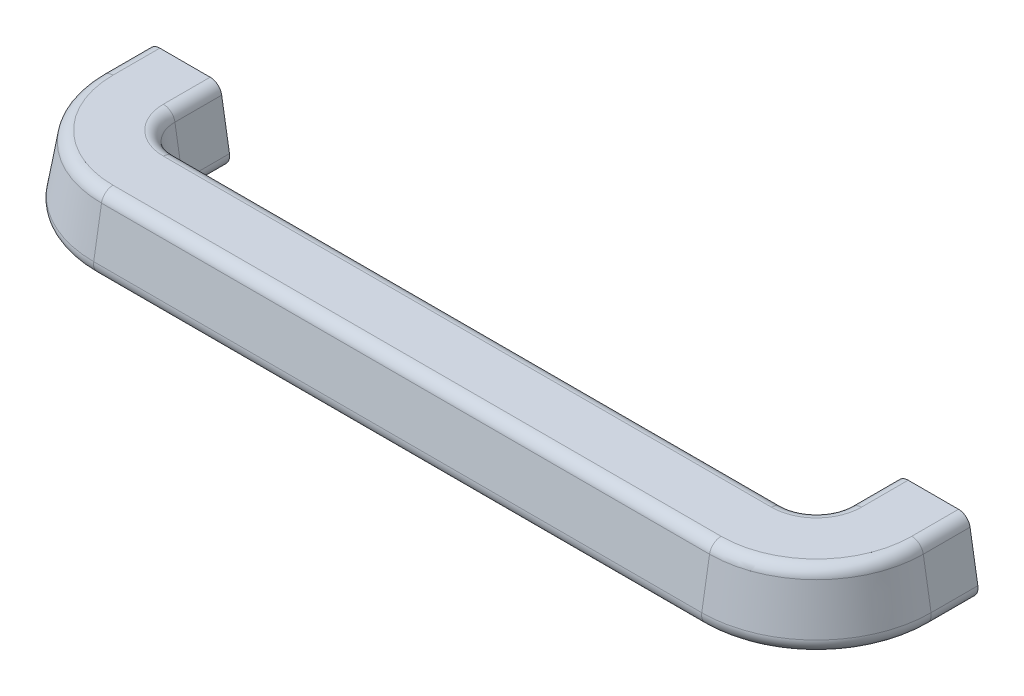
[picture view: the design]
ISO-10303-21;
HEADER;
FILE_DESCRIPTION(('STEP AP214'),'2;1');
FILE_NAME('part.step','',(''),(''),'','','');
FILE_SCHEMA(('AUTOMOTIVE_DESIGN { 1 0 10303 214 1 1 1 1 }'));
ENDSEC;
DATA;
#1=APPLICATION_CONTEXT('core data for automotive mechanical design processes');
#2=APPLICATION_PROTOCOL_DEFINITION('international standard','automotive_design',2000,#1);
#3=PRODUCT_CONTEXT('',#1,'mechanical');
#4=PRODUCT('Part','Part','',(#3));
#5=PRODUCT_RELATED_PRODUCT_CATEGORY('part','',(#4));
#6=PRODUCT_DEFINITION_FORMATION('','',#4);
#7=PRODUCT_DEFINITION_CONTEXT('part definition',#1,'design');
#8=PRODUCT_DEFINITION('design','',#6,#7);
#9=PRODUCT_DEFINITION_SHAPE('','',#8);
#10=(LENGTH_UNIT() NAMED_UNIT(*) SI_UNIT(.MILLI.,.METRE.));
#11=(NAMED_UNIT(*) PLANE_ANGLE_UNIT() SI_UNIT($,.RADIAN.));
#12=(NAMED_UNIT(*) SI_UNIT($,.STERADIAN.) SOLID_ANGLE_UNIT());
#13=UNCERTAINTY_MEASURE_WITH_UNIT(LENGTH_MEASURE(1.E-05),#10,'distance_accuracy_value','');
#14=(GEOMETRIC_REPRESENTATION_CONTEXT(3) GLOBAL_UNCERTAINTY_ASSIGNED_CONTEXT((#13)) GLOBAL_UNIT_ASSIGNED_CONTEXT((#10,
#11,#12)) REPRESENTATION_CONTEXT('',''));
#15=CARTESIAN_POINT('',(0.,0.,0.));
#16=DIRECTION('',(0.,0.,1.));
#17=DIRECTION('',(1.,0.,0.));
#18=AXIS2_PLACEMENT_3D('',#15,#16,#17);
#19=CARTESIAN_POINT('',(-189.529257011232,12.7,-38.1));
#20=DIRECTION('',(0.,0.,-1.));
#21=DIRECTION('',(-1.,0.,0.));
#22=AXIS2_PLACEMENT_3D('',#19,#20,#21);
#23=CYLINDRICAL_SURFACE('',#22,6.35);
#24=CARTESIAN_POINT('',(-189.529257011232,12.7,-38.1));
#25=DIRECTION('',(0.,0.,1.));
#26=DIRECTION('',(-1.,0.,0.));
#27=AXIS2_PLACEMENT_3D('',#24,#25,#26);
#28=CIRCLE('',#27,6.35);
#29=CARTESIAN_POINT('',(-183.265655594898,13.743933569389,-38.1));
#30=VERTEX_POINT('',#29);
#31=CARTESIAN_POINT('',(-189.529257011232,19.05,-38.1));
#32=VERTEX_POINT('',#31);
#33=EDGE_CURVE('E505',#30,#32,#28,.T.);
#34=ORIENTED_EDGE('',*,*,#33,.F.);
#35=DIRECTION('',(0.,0.,-1.));
#36=VECTOR('',#35,1.);
#37=CARTESIAN_POINT('',(-183.265655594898,13.743933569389,-38.1));
#38=LINE('',#37,#36);
#39=CARTESIAN_POINT('',(-183.265655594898,13.743933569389,-63.5));
#40=VERTEX_POINT('',#39);
#41=EDGE_CURVE('E595',#30,#40,#38,.T.);
#42=ORIENTED_EDGE('',*,*,#41,.T.);
#43=CARTESIAN_POINT('',(-189.529257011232,12.7,-63.5));
#44=DIRECTION('',(0.,0.,1.));
#45=DIRECTION('',(-1.,0.,0.));
#46=AXIS2_PLACEMENT_3D('',#43,#44,#45);
#47=CIRCLE('',#46,6.35);
#48=CARTESIAN_POINT('',(-189.529257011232,19.05,-63.5));
#49=VERTEX_POINT('',#48);
#50=EDGE_CURVE('E56',#40,#49,#47,.T.);
#51=ORIENTED_EDGE('',*,*,#50,.T.);
#52=DIRECTION('',(0.,0.,-1.));
#53=VECTOR('',#52,1.);
#54=CARTESIAN_POINT('',(-189.529257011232,19.05,-38.1));
#55=LINE('',#54,#53);
#56=EDGE_CURVE('E41',#32,#49,#55,.T.);
#57=ORIENTED_EDGE('',*,*,#56,.F.);
#58=EDGE_LOOP('',(#34,#42,#51,#57));
#59=FACE_BOUND('',#58,.T.);
#60=ADVANCED_FACE('F34',(#59),#23,.T.);
#61=CARTESIAN_POINT('',(-179.032322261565,-11.656066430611,-38.0999999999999));
#62=DIRECTION('',(-0.986393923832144,-0.164398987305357,0.));
#63=DIRECTION('',(0.164398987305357,-0.986393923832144,0.));
#64=AXIS2_PLACEMENT_3D('',#61,#62,#63);
#65=PLANE('',#64);
#66=DIRECTION('',(-0.164398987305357,0.986393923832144,0.));
#67=VECTOR('',#66,1.);
#68=CARTESIAN_POINT('',(-179.032322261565,-11.656066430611,-38.0999999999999));
#69=LINE('',#68,#67);
#70=CARTESIAN_POINT('',(-179.032322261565,-11.656066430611,-38.0999999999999));
#71=VERTEX_POINT('',#70);
#72=EDGE_CURVE('E502',#71,#30,#69,.T.);
#73=ORIENTED_EDGE('',*,*,#72,.F.);
#74=DIRECTION('',(0.,0.,-1.));
#75=VECTOR('',#74,1.);
#76=CARTESIAN_POINT('',(-179.032322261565,-11.656066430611,-38.0999999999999));
#77=LINE('',#76,#75);
#78=CARTESIAN_POINT('',(-179.032322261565,-11.656066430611,-63.4999999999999));
#79=VERTEX_POINT('',#78);
#80=EDGE_CURVE('E592',#71,#79,#77,.T.);
#81=ORIENTED_EDGE('',*,*,#80,.T.);
#82=DIRECTION('',(-0.164398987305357,0.986393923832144,0.));
#83=VECTOR('',#82,1.);
#84=CARTESIAN_POINT('',(-179.032322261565,-11.656066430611,-63.4999999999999));
#85=LINE('',#84,#83);
#86=EDGE_CURVE('E566',#79,#40,#85,.T.);
#87=ORIENTED_EDGE('',*,*,#86,.T.);
#88=ORIENTED_EDGE('',*,*,#41,.F.);
#89=EDGE_LOOP('',(#73,#81,#87,#88));
#90=FACE_BOUND('',#89,.T.);
#91=ADVANCED_FACE('F607',(#90),#65,.F.);
#92=CARTESIAN_POINT('',(-185.295923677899,-12.7,-38.1));
#93=DIRECTION('',(0.,0.,-1.));
#94=DIRECTION('',(-1.,0.,0.));
#95=AXIS2_PLACEMENT_3D('',#92,#93,#94);
#96=CYLINDRICAL_SURFACE('',#95,6.35);
#97=CARTESIAN_POINT('',(-185.295923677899,-12.7,-38.1));
#98=DIRECTION('',(0.,0.,1.));
#99=DIRECTION('',(1.,0.,0.));
#100=AXIS2_PLACEMENT_3D('',#97,#98,#99);
#101=CIRCLE('',#100,6.35);
#102=CARTESIAN_POINT('',(-185.295923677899,-19.05,-38.1));
#103=VERTEX_POINT('',#102);
#104=EDGE_CURVE('E499',#103,#71,#101,.T.);
#105=ORIENTED_EDGE('',*,*,#104,.F.);
#106=DIRECTION('',(0.,0.,-1.));
#107=VECTOR('',#106,1.);
#108=CARTESIAN_POINT('',(-185.295923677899,-19.05,-38.1));
#109=LINE('',#108,#107);
#110=CARTESIAN_POINT('',(-185.295923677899,-19.05,-63.5));
#111=VERTEX_POINT('',#110);
#112=EDGE_CURVE('E589',#103,#111,#109,.T.);
#113=ORIENTED_EDGE('',*,*,#112,.T.);
#114=CARTESIAN_POINT('',(-185.295923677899,-12.7,-63.5));
#115=DIRECTION('',(0.,0.,1.));
#116=DIRECTION('',(1.,0.,0.));
#117=AXIS2_PLACEMENT_3D('',#114,#115,#116);
#118=CIRCLE('',#117,6.35);
#119=EDGE_CURVE('E564',#111,#79,#118,.T.);
#120=ORIENTED_EDGE('',*,*,#119,.T.);
#121=ORIENTED_EDGE('',*,*,#80,.F.);
#122=EDGE_LOOP('',(#105,#113,#120,#121));
#123=FACE_BOUND('',#122,.T.);
#124=ADVANCED_FACE('F613',(#123),#96,.T.);
#125=CARTESIAN_POINT('',(-221.104076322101,-12.7,-38.1000000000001));
#126=DIRECTION('',(0.,0.,-1.));
#127=DIRECTION('',(-1.,0.,0.));
#128=AXIS2_PLACEMENT_3D('',#125,#126,#127);
#129=CYLINDRICAL_SURFACE('',#128,6.35);
#130=CARTESIAN_POINT('',(-221.104076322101,-12.7,-38.1000000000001));
#131=DIRECTION('',(0.,0.,1.));
#132=DIRECTION('',(-1.,0.,0.));
#133=AXIS2_PLACEMENT_3D('',#130,#131,#132);
#134=CIRCLE('',#133,6.35);
#135=CARTESIAN_POINT('',(-227.367677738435,-11.656066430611,-38.1000000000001));
#136=VERTEX_POINT('',#135);
#137=CARTESIAN_POINT('',(-221.104076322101,-19.05,-38.1000000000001));
#138=VERTEX_POINT('',#137);
#139=EDGE_CURVE('E496',#136,#138,#134,.T.);
#140=ORIENTED_EDGE('',*,*,#139,.F.);
#141=DIRECTION('',(0.,0.,-1.));
#142=VECTOR('',#141,1.);
#143=CARTESIAN_POINT('',(-227.367677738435,-11.656066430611,-38.1000000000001));
#144=LINE('',#143,#142);
#145=CARTESIAN_POINT('',(-227.367677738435,-11.656066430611,-63.5000000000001));
#146=VERTEX_POINT('',#145);
#147=EDGE_CURVE('E583',#136,#146,#144,.T.);
#148=ORIENTED_EDGE('',*,*,#147,.T.);
#149=CARTESIAN_POINT('',(-221.104076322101,-12.7,-63.5000000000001));
#150=DIRECTION('',(0.,0.,1.));
#151=DIRECTION('',(-1.,0.,0.));
#152=AXIS2_PLACEMENT_3D('',#149,#150,#151);
#153=CIRCLE('',#152,6.35);
#154=CARTESIAN_POINT('',(-221.104076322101,-19.05,-63.5000000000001));
#155=VERTEX_POINT('',#154);
#156=EDGE_CURVE('E560',#146,#155,#153,.T.);
#157=ORIENTED_EDGE('',*,*,#156,.T.);
#158=DIRECTION('',(0.,0.,-1.));
#159=VECTOR('',#158,1.);
#160=CARTESIAN_POINT('',(-221.104076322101,-19.05,-38.1000000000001));
#161=LINE('',#160,#159);
#162=EDGE_CURVE('E586',#138,#155,#161,.T.);
#163=ORIENTED_EDGE('',*,*,#162,.F.);
#164=EDGE_LOOP('',(#140,#148,#157,#163));
#165=FACE_BOUND('',#164,.T.);
#166=ADVANCED_FACE('F672',(#165),#129,.T.);
#167=CARTESIAN_POINT('',(-223.134344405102,13.743933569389,-38.1000000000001));
#168=DIRECTION('',(0.986393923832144,-0.164398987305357,0.));
#169=DIRECTION('',(0.164398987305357,0.986393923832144,0.));
#170=AXIS2_PLACEMENT_3D('',#167,#168,#169);
#171=PLANE('',#170);
#172=DIRECTION('',(-0.164398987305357,-0.986393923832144,0.));
#173=VECTOR('',#172,1.);
#174=CARTESIAN_POINT('',(-223.134344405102,13.743933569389,-38.1000000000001));
#175=LINE('',#174,#173);
#176=CARTESIAN_POINT('',(-223.134344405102,13.743933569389,-38.1000000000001));
#177=VERTEX_POINT('',#176);
#178=EDGE_CURVE('E492',#177,#136,#175,.T.);
#179=ORIENTED_EDGE('',*,*,#178,.F.);
#180=DIRECTION('',(0.,0.,-1.));
#181=VECTOR('',#180,1.);
#182=CARTESIAN_POINT('',(-223.134344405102,13.743933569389,-38.1000000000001));
#183=LINE('',#182,#181);
#184=CARTESIAN_POINT('',(-223.134344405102,13.743933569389,-63.5000000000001));
#185=VERTEX_POINT('',#184);
#186=EDGE_CURVE('E570',#177,#185,#183,.T.);
#187=ORIENTED_EDGE('',*,*,#186,.T.);
#188=DIRECTION('',(-0.164398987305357,-0.986393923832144,0.));
#189=VECTOR('',#188,1.);
#190=CARTESIAN_POINT('',(-223.134344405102,13.743933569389,-63.5000000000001));
#191=LINE('',#190,#189);
#192=EDGE_CURVE('E557',#185,#146,#191,.T.);
#193=ORIENTED_EDGE('',*,*,#192,.T.);
#194=ORIENTED_EDGE('',*,*,#147,.F.);
#195=EDGE_LOOP('',(#179,#187,#193,#194));
#196=FACE_BOUND('',#195,.T.);
#197=ADVANCED_FACE('F675',(#196),#171,.F.);
#198=CARTESIAN_POINT('',(-216.870742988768,12.7,-38.1));
#199=DIRECTION('',(0.,0.,-1.));
#200=DIRECTION('',(-1.,0.,0.));
#201=AXIS2_PLACEMENT_3D('',#198,#199,#200);
#202=CYLINDRICAL_SURFACE('',#201,6.35);
#203=CARTESIAN_POINT('',(-216.870742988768,12.7,-38.1));
#204=DIRECTION('',(0.,0.,1.));
#205=DIRECTION('',(1.,0.,0.));
#206=AXIS2_PLACEMENT_3D('',#203,#204,#205);
#207=CIRCLE('',#206,6.35);
#208=CARTESIAN_POINT('',(-216.870742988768,19.05,-38.1));
#209=VERTEX_POINT('',#208);
#210=EDGE_CURVE('E489',#209,#177,#207,.T.);
#211=ORIENTED_EDGE('',*,*,#210,.F.);
#212=DIRECTION('',(0.,0.,-1.));
#213=VECTOR('',#212,1.);
#214=CARTESIAN_POINT('',(-216.870742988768,19.05,-38.1));
#215=LINE('',#214,#213);
#216=CARTESIAN_POINT('',(-216.870742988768,19.05,-63.5));
#217=VERTEX_POINT('',#216);
#218=EDGE_CURVE('E11',#209,#217,#215,.T.);
#219=ORIENTED_EDGE('',*,*,#218,.T.);
#220=CARTESIAN_POINT('',(-216.870742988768,12.7,-63.5));
#221=DIRECTION('',(0.,0.,1.));
#222=DIRECTION('',(1.,0.,0.));
#223=AXIS2_PLACEMENT_3D('',#220,#221,#222);
#224=CIRCLE('',#223,6.35);
#225=EDGE_CURVE('E555',#217,#185,#224,.T.);
#226=ORIENTED_EDGE('',*,*,#225,.T.);
#227=ORIENTED_EDGE('',*,*,#186,.F.);
#228=EDGE_LOOP('',(#211,#219,#226,#227));
#229=FACE_BOUND('',#228,.T.);
#230=ADVANCED_FACE('F623',(#229),#202,.T.);
#231=CARTESIAN_POINT('',(-215.9,-12.7,-38.1));
#232=DIRECTION('',(1.,0.,0.));
#233=DIRECTION('',(0.,0.,-1.));
#234=AXIS2_PLACEMENT_3D('',#231,#232,#233);
#235=PLANE('',#234);
#236=DIRECTION('',(0.,-1.,0.));
#237=VECTOR('',#236,1.);
#238=CARTESIAN_POINT('',(-215.9,-12.7,-38.1));
#239=LINE('',#238,#237);
#240=CARTESIAN_POINT('',(-215.9,12.7,-38.1));
#241=VERTEX_POINT('',#240);
#242=CARTESIAN_POINT('',(-215.9,-12.7,-38.1));
#243=VERTEX_POINT('',#242);
#244=EDGE_CURVE('E485',#241,#243,#239,.T.);
#245=ORIENTED_EDGE('',*,*,#244,.T.);
#246=DIRECTION('',(0.,0.,-1.));
#247=VECTOR('',#246,1.);
#248=CARTESIAN_POINT('',(-215.9,-12.7,-38.1));
#249=LINE('',#248,#247);
#250=CARTESIAN_POINT('',(-215.9,-12.7,-63.5));
#251=VERTEX_POINT('',#250);
#252=EDGE_CURVE('E573',#243,#251,#249,.T.);
#253=ORIENTED_EDGE('',*,*,#252,.T.);
#254=DIRECTION('',(0.,-1.,0.));
#255=VECTOR('',#254,1.);
#256=CARTESIAN_POINT('',(-215.9,-12.7,-63.5));
#257=LINE('',#256,#255);
#258=CARTESIAN_POINT('',(-215.9,12.7,-63.5));
#259=VERTEX_POINT('',#258);
#260=EDGE_CURVE('E548',#259,#251,#257,.T.);
#261=ORIENTED_EDGE('',*,*,#260,.F.);
#262=DIRECTION('',(0.,0.,-1.));
#263=VECTOR('',#262,1.);
#264=CARTESIAN_POINT('',(-215.9,12.7,-38.1));
#265=LINE('',#264,#263);
#266=EDGE_CURVE('E576',#241,#259,#265,.T.);
#267=ORIENTED_EDGE('',*,*,#266,.F.);
#268=EDGE_LOOP('',(#245,#253,#261,#267));
#269=FACE_BOUND('',#268,.T.);
#270=ADVANCED_FACE('F727',(#269),#235,.T.);
#271=CARTESIAN_POINT('',(-190.5,-12.7,-38.1));
#272=DIRECTION('',(-1.,0.,0.));
#273=DIRECTION('',(0.,0.,1.));
#274=AXIS2_PLACEMENT_3D('',#271,#272,#273);
#275=PLANE('',#274);
#276=DIRECTION('',(0.,1.,0.));
#277=VECTOR('',#276,1.);
#278=CARTESIAN_POINT('',(-190.5,-12.7,-38.1));
#279=LINE('',#278,#277);
#280=CARTESIAN_POINT('',(-190.5,-12.7,-38.1));
#281=VERTEX_POINT('',#280);
#282=CARTESIAN_POINT('',(-190.5,12.7,-38.1));
#283=VERTEX_POINT('',#282);
#284=EDGE_CURVE('E482',#281,#283,#279,.T.);
#285=ORIENTED_EDGE('',*,*,#284,.T.);
#286=DIRECTION('',(0.,0.,-1.));
#287=VECTOR('',#286,1.);
#288=CARTESIAN_POINT('',(-190.5,12.7,-38.1));
#289=LINE('',#288,#287);
#290=CARTESIAN_POINT('',(-190.5,12.7,-63.5));
#291=VERTEX_POINT('',#290);
#292=EDGE_CURVE('E558',#283,#291,#289,.T.);
#293=ORIENTED_EDGE('',*,*,#292,.T.);
#294=DIRECTION('',(0.,1.,0.));
#295=VECTOR('',#294,1.);
#296=CARTESIAN_POINT('',(-190.5,-12.7,-63.5));
#297=LINE('',#296,#295);
#298=CARTESIAN_POINT('',(-190.5,-12.7,-63.5));
#299=VERTEX_POINT('',#298);
#300=EDGE_CURVE('E542',#299,#291,#297,.T.);
#301=ORIENTED_EDGE('',*,*,#300,.F.);
#302=DIRECTION('',(0.,0.,-1.));
#303=VECTOR('',#302,1.);
#304=CARTESIAN_POINT('',(-190.5,-12.7,-38.1));
#305=LINE('',#304,#303);
#306=EDGE_CURVE('E554',#281,#299,#305,.T.);
#307=ORIENTED_EDGE('',*,*,#306,.F.);
#308=EDGE_LOOP('',(#285,#293,#301,#307));
#309=FACE_BOUND('',#308,.T.);
#310=ADVANCED_FACE('F730',(#309),#275,.T.);
#311=CARTESIAN_POINT('',(-165.1,12.7,-38.1));
#312=DIRECTION('',(0.,-1.,0.));
#313=DIRECTION('',(0.,0.,-1.));
#314=AXIS2_PLACEMENT_3D('',#311,#312,#313);
#315=TOROIDAL_SURFACE('',#314,24.4292570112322,6.35);
#316=CARTESIAN_POINT('',(-165.1,12.7,-13.6707429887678));
#317=DIRECTION('',(1.,0.,0.));
#318=DIRECTION('',(0.,0.,1.));
#319=AXIS2_PLACEMENT_3D('',#316,#317,#318);
#320=CIRCLE('',#319,6.35);
#321=CARTESIAN_POINT('',(-165.1,13.743933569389,-19.9343444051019));
#322=VERTEX_POINT('',#321);
#323=CARTESIAN_POINT('',(-165.1,19.05,-13.6707429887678));
#324=VERTEX_POINT('',#323);
#325=EDGE_CURVE('E446',#322,#324,#320,.T.);
#326=ORIENTED_EDGE('',*,*,#325,.F.);
#327=CARTESIAN_POINT('',(-165.1,13.743933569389,-38.1));
#328=DIRECTION('',(0.,-1.,0.));
#329=DIRECTION('',(0.,0.,-1.));
#330=AXIS2_PLACEMENT_3D('',#327,#328,#329);
#331=CIRCLE('',#330,18.1656555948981);
#332=EDGE_CURVE('E533',#322,#30,#331,.T.);
#333=ORIENTED_EDGE('',*,*,#332,.T.);
#334=ORIENTED_EDGE('',*,*,#33,.T.);
#335=CARTESIAN_POINT('',(-165.1,19.05,-38.1));
#336=DIRECTION('',(0.,-1.,0.));
#337=DIRECTION('',(0.,0.,-1.));
#338=AXIS2_PLACEMENT_3D('',#335,#336,#337);
#339=CIRCLE('',#338,24.4292570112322);
#340=EDGE_CURVE('E536',#324,#32,#339,.T.);
#341=ORIENTED_EDGE('',*,*,#340,.F.);
#342=EDGE_LOOP('',(#326,#333,#334,#341));
#343=FACE_BOUND('',#342,.T.);
#344=ADVANCED_FACE('F601',(#343),#315,.T.);
#345=CARTESIAN_POINT('',(-165.1,-11.656066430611,-38.1));
#346=DIRECTION('',(0.,1.,0.));
#347=DIRECTION('',(0.,0.,1.));
#348=AXIS2_PLACEMENT_3D('',#345,#346,#347);
#349=CONICAL_SURFACE('',#348,13.9323222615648,0.165148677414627);
#350=DIRECTION('',(0.,0.986393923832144,0.164398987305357));
#351=VECTOR('',#350,1.);
#352=CARTESIAN_POINT('',(-165.1,-11.656066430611,-24.1676777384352));
#353=LINE('',#352,#351);
#354=CARTESIAN_POINT('',(-165.1,-11.656066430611,-24.1676777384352));
#355=VERTEX_POINT('',#354);
#356=EDGE_CURVE('E443',#355,#322,#353,.T.);
#357=ORIENTED_EDGE('',*,*,#356,.F.);
#358=CARTESIAN_POINT('',(-165.1,-11.656066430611,-38.1));
#359=DIRECTION('',(0.,-1.,0.));
#360=DIRECTION('',(0.,0.,-1.));
#361=AXIS2_PLACEMENT_3D('',#358,#359,#360);
#362=CIRCLE('',#361,13.9323222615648);
#363=EDGE_CURVE('E530',#355,#71,#362,.T.);
#364=ORIENTED_EDGE('',*,*,#363,.T.);
#365=ORIENTED_EDGE('',*,*,#72,.T.);
#366=ORIENTED_EDGE('',*,*,#332,.F.);
#367=EDGE_LOOP('',(#357,#364,#365,#366));
#368=FACE_BOUND('',#367,.T.);
#369=ADVANCED_FACE('F604',(#368),#349,.F.);
#370=CARTESIAN_POINT('',(-165.1,-12.7,-38.1));
#371=DIRECTION('',(0.,-1.,0.));
#372=DIRECTION('',(0.,0.,-1.));
#373=AXIS2_PLACEMENT_3D('',#370,#371,#372);
#374=TOROIDAL_SURFACE('',#373,20.1959236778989,6.35);
#375=CARTESIAN_POINT('',(-165.1,-12.7,-17.9040763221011));
#376=DIRECTION('',(1.,0.,0.));
#377=DIRECTION('',(0.,0.,-1.));
#378=AXIS2_PLACEMENT_3D('',#375,#376,#377);
#379=CIRCLE('',#378,6.35);
#380=CARTESIAN_POINT('',(-165.1,-19.05,-17.9040763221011));
#381=VERTEX_POINT('',#380);
#382=EDGE_CURVE('E440',#381,#355,#379,.T.);
#383=ORIENTED_EDGE('',*,*,#382,.F.);
#384=CARTESIAN_POINT('',(-165.1,-19.05,-38.1));
#385=DIRECTION('',(0.,-1.,0.));
#386=DIRECTION('',(0.,0.,-1.));
#387=AXIS2_PLACEMENT_3D('',#384,#385,#386);
#388=CIRCLE('',#387,20.1959236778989);
#389=EDGE_CURVE('E527',#381,#103,#388,.T.);
#390=ORIENTED_EDGE('',*,*,#389,.T.);
#391=ORIENTED_EDGE('',*,*,#104,.T.);
#392=ORIENTED_EDGE('',*,*,#363,.F.);
#393=EDGE_LOOP('',(#383,#390,#391,#392));
#394=FACE_BOUND('',#393,.T.);
#395=ADVANCED_FACE('F611',(#394),#374,.T.);
#396=CARTESIAN_POINT('',(-165.1,-12.7,-38.1));
#397=DIRECTION('',(0.,-1.,0.));
#398=DIRECTION('',(0.,0.,-1.));
#399=AXIS2_PLACEMENT_3D('',#396,#397,#398);
#400=TOROIDAL_SURFACE('',#399,56.004076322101,6.35);
#401=CARTESIAN_POINT('',(-165.1,-12.7,17.904076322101));
#402=DIRECTION('',(1.,0.,0.));
#403=DIRECTION('',(0.,0.,1.));
#404=AXIS2_PLACEMENT_3D('',#401,#402,#403);
#405=CIRCLE('',#404,6.35);
#406=CARTESIAN_POINT('',(-165.1,-11.656066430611,24.1676777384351));
#407=VERTEX_POINT('',#406);
#408=CARTESIAN_POINT('',(-165.1,-19.05,17.904076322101));
#409=VERTEX_POINT('',#408);
#410=EDGE_CURVE('E437',#407,#409,#405,.T.);
#411=ORIENTED_EDGE('',*,*,#410,.F.);
#412=CARTESIAN_POINT('',(-165.1,-11.656066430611,-38.1));
#413=DIRECTION('',(0.,-1.,0.));
#414=DIRECTION('',(0.,0.,-1.));
#415=AXIS2_PLACEMENT_3D('',#412,#413,#414);
#416=CIRCLE('',#415,62.2676777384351);
#417=EDGE_CURVE('E521',#407,#136,#416,.T.);
#418=ORIENTED_EDGE('',*,*,#417,.T.);
#419=ORIENTED_EDGE('',*,*,#139,.T.);
#420=CARTESIAN_POINT('',(-165.1,-19.05,-38.1));
#421=DIRECTION('',(0.,-1.,0.));
#422=DIRECTION('',(0.,0.,-1.));
#423=AXIS2_PLACEMENT_3D('',#420,#421,#422);
#424=CIRCLE('',#423,56.004076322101);
#425=EDGE_CURVE('E524',#409,#138,#424,.T.);
#426=ORIENTED_EDGE('',*,*,#425,.F.);
#427=EDGE_LOOP('',(#411,#418,#419,#426));
#428=FACE_BOUND('',#427,.T.);
#429=ADVANCED_FACE('F741',(#428),#400,.T.);
#430=CARTESIAN_POINT('',(-165.1,13.743933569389,-38.1));
#431=DIRECTION('',(0.,-1.,0.));
#432=DIRECTION('',(0.,0.,-1.));
#433=AXIS2_PLACEMENT_3D('',#430,#431,#432);
#434=CONICAL_SURFACE('',#433,58.0343444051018,0.165148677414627);
#435=DIRECTION('',(0.,-0.986393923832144,0.164398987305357));
#436=VECTOR('',#435,1.);
#437=CARTESIAN_POINT('',(-165.1,13.743933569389,19.9343444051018));
#438=LINE('',#437,#436);
#439=CARTESIAN_POINT('',(-165.1,13.743933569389,19.9343444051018));
#440=VERTEX_POINT('',#439);
#441=EDGE_CURVE('E433',#440,#407,#438,.T.);
#442=ORIENTED_EDGE('',*,*,#441,.F.);
#443=CARTESIAN_POINT('',(-165.1,13.743933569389,-38.1));
#444=DIRECTION('',(0.,-1.,0.));
#445=DIRECTION('',(0.,0.,-1.));
#446=AXIS2_PLACEMENT_3D('',#443,#444,#445);
#447=CIRCLE('',#446,58.0343444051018);
#448=EDGE_CURVE('E508',#440,#177,#447,.T.);
#449=ORIENTED_EDGE('',*,*,#448,.T.);
#450=ORIENTED_EDGE('',*,*,#178,.T.);
#451=ORIENTED_EDGE('',*,*,#417,.F.);
#452=EDGE_LOOP('',(#442,#449,#450,#451));
#453=FACE_BOUND('',#452,.T.);
#454=ADVANCED_FACE('F677',(#453),#434,.T.);
#455=CARTESIAN_POINT('',(-165.1,12.7,-38.1));
#456=DIRECTION('',(0.,-1.,0.));
#457=DIRECTION('',(0.,0.,-1.));
#458=AXIS2_PLACEMENT_3D('',#455,#456,#457);
#459=TOROIDAL_SURFACE('',#458,51.7707429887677,6.35);
#460=CARTESIAN_POINT('',(-165.1,12.7,13.6707429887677));
#461=DIRECTION('',(1.,0.,0.));
#462=DIRECTION('',(0.,0.,-1.));
#463=AXIS2_PLACEMENT_3D('',#460,#461,#462);
#464=CIRCLE('',#463,6.35);
#465=CARTESIAN_POINT('',(-165.1,19.05,13.6707429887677));
#466=VERTEX_POINT('',#465);
#467=EDGE_CURVE('E430',#466,#440,#464,.T.);
#468=ORIENTED_EDGE('',*,*,#467,.F.);
#469=CARTESIAN_POINT('',(-165.1,19.05,-38.1));
#470=DIRECTION('',(0.,-1.,0.));
#471=DIRECTION('',(0.,0.,-1.));
#472=AXIS2_PLACEMENT_3D('',#469,#470,#471);
#473=CIRCLE('',#472,51.7707429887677);
#474=EDGE_CURVE('E539',#466,#209,#473,.T.);
#475=ORIENTED_EDGE('',*,*,#474,.T.);
#476=ORIENTED_EDGE('',*,*,#210,.T.);
#477=ORIENTED_EDGE('',*,*,#448,.F.);
#478=EDGE_LOOP('',(#468,#475,#476,#477));
#479=FACE_BOUND('',#478,.T.);
#480=ADVANCED_FACE('F627',(#479),#459,.T.);
#481=CARTESIAN_POINT('',(-165.1,0.,-38.1));
#482=DIRECTION('',(0.,-1.,0.));
#483=DIRECTION('',(0.,0.,-1.));
#484=AXIS2_PLACEMENT_3D('',#481,#482,#483);
#485=CYLINDRICAL_SURFACE('',#484,50.8);
#486=DIRECTION('',(0.,-1.,0.));
#487=VECTOR('',#486,1.);
#488=CARTESIAN_POINT('',(-165.1,-12.7,12.7));
#489=LINE('',#488,#487);
#490=CARTESIAN_POINT('',(-165.1,12.7,12.7));
#491=VERTEX_POINT('',#490);
#492=CARTESIAN_POINT('',(-165.1,-12.7,12.7));
#493=VERTEX_POINT('',#492);
#494=EDGE_CURVE('E426',#491,#493,#489,.T.);
#495=ORIENTED_EDGE('',*,*,#494,.T.);
#496=CARTESIAN_POINT('',(-165.1,-12.7,-38.1));
#497=DIRECTION('',(0.,-1.,0.));
#498=DIRECTION('',(0.,0.,-1.));
#499=AXIS2_PLACEMENT_3D('',#496,#497,#498);
#500=CIRCLE('',#499,50.8);
#501=EDGE_CURVE('E511',#493,#243,#500,.T.);
#502=ORIENTED_EDGE('',*,*,#501,.T.);
#503=ORIENTED_EDGE('',*,*,#244,.F.);
#504=CARTESIAN_POINT('',(-165.1,12.7,-38.1));
#505=DIRECTION('',(0.,-1.,0.));
#506=DIRECTION('',(0.,0.,-1.));
#507=AXIS2_PLACEMENT_3D('',#504,#505,#506);
#508=CIRCLE('',#507,50.8);
#509=EDGE_CURVE('E514',#491,#241,#508,.T.);
#510=ORIENTED_EDGE('',*,*,#509,.F.);
#511=EDGE_LOOP('',(#495,#502,#503,#510));
#512=FACE_BOUND('',#511,.T.);
#513=ADVANCED_FACE('F749',(#512),#485,.F.);
#514=CARTESIAN_POINT('',(-165.1,0.,-38.1));
#515=DIRECTION('',(0.,-1.,0.));
#516=DIRECTION('',(0.,0.,-1.));
#517=AXIS2_PLACEMENT_3D('',#514,#515,#516);
#518=CYLINDRICAL_SURFACE('',#517,25.4000000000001);
#519=DIRECTION('',(0.,1.,0.));
#520=VECTOR('',#519,1.);
#521=CARTESIAN_POINT('',(-165.1,-12.7,-12.6999999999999));
#522=LINE('',#521,#520);
#523=CARTESIAN_POINT('',(-165.1,-12.7,-12.6999999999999));
#524=VERTEX_POINT('',#523);
#525=CARTESIAN_POINT('',(-165.1,12.7,-12.6999999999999));
#526=VERTEX_POINT('',#525);
#527=EDGE_CURVE('E423',#524,#526,#522,.T.);
#528=ORIENTED_EDGE('',*,*,#527,.T.);
#529=CARTESIAN_POINT('',(-165.1,12.7,-38.1));
#530=DIRECTION('',(0.,-1.,0.));
#531=DIRECTION('',(0.,0.,-1.));
#532=AXIS2_PLACEMENT_3D('',#529,#530,#531);
#533=CIRCLE('',#532,25.4000000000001);
#534=EDGE_CURVE('E493',#526,#283,#533,.T.);
#535=ORIENTED_EDGE('',*,*,#534,.T.);
#536=ORIENTED_EDGE('',*,*,#284,.F.);
#537=CARTESIAN_POINT('',(-165.1,-12.7,-38.1));
#538=DIRECTION('',(0.,-1.,0.));
#539=DIRECTION('',(0.,0.,-1.));
#540=AXIS2_PLACEMENT_3D('',#537,#538,#539);
#541=CIRCLE('',#540,25.4000000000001);
#542=EDGE_CURVE('E488',#524,#281,#541,.T.);
#543=ORIENTED_EDGE('',*,*,#542,.F.);
#544=EDGE_LOOP('',(#528,#535,#536,#543));
#545=FACE_BOUND('',#544,.T.);
#546=ADVANCED_FACE('F752',(#545),#518,.T.);
#547=CARTESIAN_POINT('',(165.1,12.7,-13.6707429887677));
#548=DIRECTION('',(-1.,0.,0.));
#549=DIRECTION('',(0.,0.,1.));
#550=AXIS2_PLACEMENT_3D('',#547,#548,#549);
#551=CYLINDRICAL_SURFACE('',#550,6.35);
#552=CARTESIAN_POINT('',(165.1,12.7,-13.6707429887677));
#553=DIRECTION('',(1.,0.,0.));
#554=DIRECTION('',(0.,0.,1.));
#555=AXIS2_PLACEMENT_3D('',#552,#553,#554);
#556=CIRCLE('',#555,6.35);
#557=CARTESIAN_POINT('',(165.1,13.743933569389,-19.9343444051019));
#558=VERTEX_POINT('',#557);
#559=CARTESIAN_POINT('',(165.1,19.05,-13.6707429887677));
#560=VERTEX_POINT('',#559);
#561=EDGE_CURVE('E390',#558,#560,#556,.T.);
#562=ORIENTED_EDGE('',*,*,#561,.F.);
#563=DIRECTION('',(-1.,0.,0.));
#564=VECTOR('',#563,1.);
#565=CARTESIAN_POINT('',(165.1,13.743933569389,-19.9343444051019));
#566=LINE('',#565,#564);
#567=EDGE_CURVE('E473',#558,#322,#566,.T.);
#568=ORIENTED_EDGE('',*,*,#567,.T.);
#569=ORIENTED_EDGE('',*,*,#325,.T.);
#570=DIRECTION('',(-1.,0.,0.));
#571=VECTOR('',#570,1.);
#572=CARTESIAN_POINT('',(165.1,19.05,-13.6707429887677));
#573=LINE('',#572,#571);
#574=EDGE_CURVE('E476',#560,#324,#573,.T.);
#575=ORIENTED_EDGE('',*,*,#574,.F.);
#576=EDGE_LOOP('',(#562,#568,#569,#575));
#577=FACE_BOUND('',#576,.T.);
#578=ADVANCED_FACE('F654',(#577),#551,.T.);
#579=CARTESIAN_POINT('',(165.1,-11.656066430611,-24.1676777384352));
#580=DIRECTION('',(0.,-0.164398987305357,0.986393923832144));
#581=DIRECTION('',(0.,-0.986393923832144,-0.164398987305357));
#582=AXIS2_PLACEMENT_3D('',#579,#580,#581);
#583=PLANE('',#582);
#584=DIRECTION('',(0.,0.986393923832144,0.164398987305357));
#585=VECTOR('',#584,1.);
#586=CARTESIAN_POINT('',(165.1,-11.656066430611,-24.1676777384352));
#587=LINE('',#586,#585);
#588=CARTESIAN_POINT('',(165.1,-11.656066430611,-24.1676777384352));
#589=VERTEX_POINT('',#588);
#590=EDGE_CURVE('E387',#589,#558,#587,.T.);
#591=ORIENTED_EDGE('',*,*,#590,.F.);
#592=DIRECTION('',(-1.,0.,0.));
#593=VECTOR('',#592,1.);
#594=CARTESIAN_POINT('',(165.1,-11.656066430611,-24.1676777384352));
#595=LINE('',#594,#593);
#596=EDGE_CURVE('E470',#589,#355,#595,.T.);
#597=ORIENTED_EDGE('',*,*,#596,.T.);
#598=ORIENTED_EDGE('',*,*,#356,.T.);
#599=ORIENTED_EDGE('',*,*,#567,.F.);
#600=EDGE_LOOP('',(#591,#597,#598,#599));
#601=FACE_BOUND('',#600,.T.);
#602=ADVANCED_FACE('F660',(#601),#583,.F.);
#603=CARTESIAN_POINT('',(165.1,-12.7,-17.9040763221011));
#604=DIRECTION('',(-1.,0.,0.));
#605=DIRECTION('',(0.,0.,1.));
#606=AXIS2_PLACEMENT_3D('',#603,#604,#605);
#607=CYLINDRICAL_SURFACE('',#606,6.35);
#608=CARTESIAN_POINT('',(165.1,-12.7,-17.9040763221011));
#609=DIRECTION('',(1.,0.,0.));
#610=DIRECTION('',(0.,0.,-1.));
#611=AXIS2_PLACEMENT_3D('',#608,#609,#610);
#612=CIRCLE('',#611,6.35);
#613=CARTESIAN_POINT('',(165.1,-19.05,-17.9040763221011));
#614=VERTEX_POINT('',#613);
#615=EDGE_CURVE('E384',#614,#589,#612,.T.);
#616=ORIENTED_EDGE('',*,*,#615,.F.);
#617=DIRECTION('',(-1.,0.,0.));
#618=VECTOR('',#617,1.);
#619=CARTESIAN_POINT('',(165.1,-19.05,-17.9040763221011));
#620=LINE('',#619,#618);
#621=EDGE_CURVE('E467',#614,#381,#620,.T.);
#622=ORIENTED_EDGE('',*,*,#621,.T.);
#623=ORIENTED_EDGE('',*,*,#382,.T.);
#624=ORIENTED_EDGE('',*,*,#596,.F.);
#625=EDGE_LOOP('',(#616,#622,#623,#624));
#626=FACE_BOUND('',#625,.T.);
#627=ADVANCED_FACE('F666',(#626),#607,.T.);
#628=CARTESIAN_POINT('',(165.1,-12.7,17.904076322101));
#629=DIRECTION('',(-1.,0.,0.));
#630=DIRECTION('',(0.,0.,1.));
#631=AXIS2_PLACEMENT_3D('',#628,#629,#630);
#632=CYLINDRICAL_SURFACE('',#631,6.35);
#633=CARTESIAN_POINT('',(165.1,-12.7,17.904076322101));
#634=DIRECTION('',(1.,0.,0.));
#635=DIRECTION('',(0.,0.,1.));
#636=AXIS2_PLACEMENT_3D('',#633,#634,#635);
#637=CIRCLE('',#636,6.35);
#638=CARTESIAN_POINT('',(165.1,-11.656066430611,24.1676777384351));
#639=VERTEX_POINT('',#638);
#640=CARTESIAN_POINT('',(165.1,-19.05,17.904076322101));
#641=VERTEX_POINT('',#640);
#642=EDGE_CURVE('E381',#639,#641,#637,.T.);
#643=ORIENTED_EDGE('',*,*,#642,.F.);
#644=DIRECTION('',(-1.,0.,0.));
#645=VECTOR('',#644,1.);
#646=CARTESIAN_POINT('',(165.1,-11.656066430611,24.1676777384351));
#647=LINE('',#646,#645);
#648=EDGE_CURVE('E461',#639,#407,#647,.T.);
#649=ORIENTED_EDGE('',*,*,#648,.T.);
#650=ORIENTED_EDGE('',*,*,#410,.T.);
#651=DIRECTION('',(-1.,0.,0.));
#652=VECTOR('',#651,1.);
#653=CARTESIAN_POINT('',(165.1,-19.05,17.904076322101));
#654=LINE('',#653,#652);
#655=EDGE_CURVE('E464',#641,#409,#654,.T.);
#656=ORIENTED_EDGE('',*,*,#655,.F.);
#657=EDGE_LOOP('',(#643,#649,#650,#656));
#658=FACE_BOUND('',#657,.T.);
#659=ADVANCED_FACE('F683',(#658),#632,.T.);
#660=CARTESIAN_POINT('',(165.1,13.743933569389,19.9343444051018));
#661=DIRECTION('',(0.,-0.164398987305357,-0.986393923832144));
#662=DIRECTION('',(0.,0.986393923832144,-0.164398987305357));
#663=AXIS2_PLACEMENT_3D('',#660,#661,#662);
#664=PLANE('',#663);
#665=DIRECTION('',(0.,-0.986393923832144,0.164398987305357));
#666=VECTOR('',#665,1.);
#667=CARTESIAN_POINT('',(165.1,13.743933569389,19.9343444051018));
#668=LINE('',#667,#666);
#669=CARTESIAN_POINT('',(165.1,13.743933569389,19.9343444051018));
#670=VERTEX_POINT('',#669);
#671=EDGE_CURVE('E377',#670,#639,#668,.T.);
#672=ORIENTED_EDGE('',*,*,#671,.F.);
#673=DIRECTION('',(-1.,0.,0.));
#674=VECTOR('',#673,1.);
#675=CARTESIAN_POINT('',(165.1,13.743933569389,19.9343444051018));
#676=LINE('',#675,#674);
#677=EDGE_CURVE('E449',#670,#440,#676,.T.);
#678=ORIENTED_EDGE('',*,*,#677,.T.);
#679=ORIENTED_EDGE('',*,*,#441,.T.);
#680=ORIENTED_EDGE('',*,*,#648,.F.);
#681=EDGE_LOOP('',(#672,#678,#679,#680));
#682=FACE_BOUND('',#681,.T.);
#683=ADVANCED_FACE('F680',(#682),#664,.F.);
#684=CARTESIAN_POINT('',(165.1,12.7,13.6707429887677));
#685=DIRECTION('',(-1.,0.,0.));
#686=DIRECTION('',(0.,0.,1.));
#687=AXIS2_PLACEMENT_3D('',#684,#685,#686);
#688=CYLINDRICAL_SURFACE('',#687,6.35);
#689=CARTESIAN_POINT('',(165.1,12.7,13.6707429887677));
#690=DIRECTION('',(1.,0.,0.));
#691=DIRECTION('',(0.,0.,-1.));
#692=AXIS2_PLACEMENT_3D('',#689,#690,#691);
#693=CIRCLE('',#692,6.35);
#694=CARTESIAN_POINT('',(165.1,19.05,13.6707429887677));
#695=VERTEX_POINT('',#694);
#696=EDGE_CURVE('E374',#695,#670,#693,.T.);
#697=ORIENTED_EDGE('',*,*,#696,.F.);
#698=DIRECTION('',(-1.,0.,0.));
#699=VECTOR('',#698,1.);
#700=CARTESIAN_POINT('',(165.1,19.05,13.6707429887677));
#701=LINE('',#700,#699);
#702=EDGE_CURVE('E479',#695,#466,#701,.T.);
#703=ORIENTED_EDGE('',*,*,#702,.T.);
#704=ORIENTED_EDGE('',*,*,#467,.T.);
#705=ORIENTED_EDGE('',*,*,#677,.F.);
#706=EDGE_LOOP('',(#697,#703,#704,#705));
#707=FACE_BOUND('',#706,.T.);
#708=ADVANCED_FACE('F630',(#707),#688,.T.);
#709=CARTESIAN_POINT('',(165.1,-12.7,12.7000000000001));
#710=DIRECTION('',(0.,0.,-1.));
#711=DIRECTION('',(-1.,0.,0.));
#712=AXIS2_PLACEMENT_3D('',#709,#710,#711);
#713=PLANE('',#712);
#714=DIRECTION('',(0.,-1.,0.));
#715=VECTOR('',#714,1.);
#716=CARTESIAN_POINT('',(165.1,-12.7,12.7000000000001));
#717=LINE('',#716,#715);
#718=CARTESIAN_POINT('',(165.1,12.7,12.7000000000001));
#719=VERTEX_POINT('',#718);
#720=CARTESIAN_POINT('',(165.1,-12.7,12.7000000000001));
#721=VERTEX_POINT('',#720);
#722=EDGE_CURVE('E280',#719,#721,#717,.T.);
#723=ORIENTED_EDGE('',*,*,#722,.T.);
#724=DIRECTION('',(-1.,0.,0.));
#725=VECTOR('',#724,1.);
#726=CARTESIAN_POINT('',(165.1,-12.7,12.7000000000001));
#727=LINE('',#726,#725);
#728=EDGE_CURVE('E451',#721,#493,#727,.T.);
#729=ORIENTED_EDGE('',*,*,#728,.T.);
#730=ORIENTED_EDGE('',*,*,#494,.F.);
#731=DIRECTION('',(-1.,0.,0.));
#732=VECTOR('',#731,1.);
#733=CARTESIAN_POINT('',(165.1,12.7,12.7000000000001));
#734=LINE('',#733,#732);
#735=EDGE_CURVE('E454',#719,#491,#734,.T.);
#736=ORIENTED_EDGE('',*,*,#735,.F.);
#737=EDGE_LOOP('',(#723,#729,#730,#736));
#738=FACE_BOUND('',#737,.T.);
#739=ADVANCED_FACE('F769',(#738),#713,.T.);
#740=CARTESIAN_POINT('',(165.1,-12.7,-12.6999999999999));
#741=DIRECTION('',(0.,0.,1.));
#742=DIRECTION('',(1.,0.,0.));
#743=AXIS2_PLACEMENT_3D('',#740,#741,#742);
#744=PLANE('',#743);
#745=DIRECTION('',(0.,1.,0.));
#746=VECTOR('',#745,1.);
#747=CARTESIAN_POINT('',(165.1,-12.7,-12.6999999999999));
#748=LINE('',#747,#746);
#749=CARTESIAN_POINT('',(165.1,-12.7,-12.6999999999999));
#750=VERTEX_POINT('',#749);
#751=CARTESIAN_POINT('',(165.1,12.7,-12.6999999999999));
#752=VERTEX_POINT('',#751);
#753=EDGE_CURVE('E276',#750,#752,#748,.T.);
#754=ORIENTED_EDGE('',*,*,#753,.T.);
#755=DIRECTION('',(-1.,0.,0.));
#756=VECTOR('',#755,1.);
#757=CARTESIAN_POINT('',(165.1,12.7,-12.6999999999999));
#758=LINE('',#757,#756);
#759=EDGE_CURVE('E434',#752,#526,#758,.T.);
#760=ORIENTED_EDGE('',*,*,#759,.T.);
#761=ORIENTED_EDGE('',*,*,#527,.F.);
#762=DIRECTION('',(-1.,0.,0.));
#763=VECTOR('',#762,1.);
#764=CARTESIAN_POINT('',(165.1,-12.7,-12.6999999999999));
#765=LINE('',#764,#763);
#766=EDGE_CURVE('E429',#750,#524,#765,.T.);
#767=ORIENTED_EDGE('',*,*,#766,.F.);
#768=EDGE_LOOP('',(#754,#760,#761,#767));
#769=FACE_BOUND('',#768,.T.);
#770=ADVANCED_FACE('F772',(#769),#744,.T.);
#771=CARTESIAN_POINT('',(165.1,12.7,-38.1));
#772=DIRECTION('',(0.,-1.,0.));
#773=DIRECTION('',(0.,0.,-1.));
#774=AXIS2_PLACEMENT_3D('',#771,#772,#773);
#775=TOROIDAL_SURFACE('',#774,24.4292570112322,6.35);
#776=CARTESIAN_POINT('',(189.529257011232,12.7,-38.1));
#777=DIRECTION('',(0.,0.,-1.));
#778=DIRECTION('',(1.,0.,0.));
#779=AXIS2_PLACEMENT_3D('',#776,#777,#778);
#780=CIRCLE('',#779,6.35);
#781=CARTESIAN_POINT('',(183.265655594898,13.743933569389,-38.1));
#782=VERTEX_POINT('',#781);
#783=CARTESIAN_POINT('',(189.529257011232,19.05,-38.1));
#784=VERTEX_POINT('',#783);
#785=EDGE_CURVE('E292',#782,#784,#780,.T.);
#786=ORIENTED_EDGE('',*,*,#785,.F.);
#787=CARTESIAN_POINT('',(165.1,13.743933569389,-38.1));
#788=DIRECTION('',(0.,-1.,0.));
#789=DIRECTION('',(0.,0.,-1.));
#790=AXIS2_PLACEMENT_3D('',#787,#788,#789);
#791=CIRCLE('',#790,18.1656555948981);
#792=EDGE_CURVE('E414',#782,#558,#791,.T.);
#793=ORIENTED_EDGE('',*,*,#792,.T.);
#794=ORIENTED_EDGE('',*,*,#561,.T.);
#795=CARTESIAN_POINT('',(165.1,19.05,-38.1));
#796=DIRECTION('',(0.,-1.,0.));
#797=DIRECTION('',(0.,0.,-1.));
#798=AXIS2_PLACEMENT_3D('',#795,#796,#797);
#799=CIRCLE('',#798,24.4292570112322);
#800=EDGE_CURVE('E417',#784,#560,#799,.T.);
#801=ORIENTED_EDGE('',*,*,#800,.F.);
#802=EDGE_LOOP('',(#786,#793,#794,#801));
#803=FACE_BOUND('',#802,.T.);
#804=ADVANCED_FACE('F651',(#803),#775,.T.);
#805=CARTESIAN_POINT('',(165.1,-11.656066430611,-38.1));
#806=DIRECTION('',(0.,1.,0.));
#807=DIRECTION('',(0.,0.,1.));
#808=AXIS2_PLACEMENT_3D('',#805,#806,#807);
#809=CONICAL_SURFACE('',#808,13.9323222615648,0.165148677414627);
#810=DIRECTION('',(0.164398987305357,0.986393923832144,0.));
#811=VECTOR('',#810,1.);
#812=CARTESIAN_POINT('',(179.032322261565,-11.656066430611,-38.1000000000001));
#813=LINE('',#812,#811);
#814=CARTESIAN_POINT('',(179.032322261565,-11.656066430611,-38.1000000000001));
#815=VERTEX_POINT('',#814);
#816=EDGE_CURVE('E318',#815,#782,#813,.T.);
#817=ORIENTED_EDGE('',*,*,#816,.F.);
#818=CARTESIAN_POINT('',(165.1,-11.656066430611,-38.1));
#819=DIRECTION('',(0.,-1.,0.));
#820=DIRECTION('',(0.,0.,-1.));
#821=AXIS2_PLACEMENT_3D('',#818,#819,#820);
#822=CIRCLE('',#821,13.9323222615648);
#823=EDGE_CURVE('E411',#815,#589,#822,.T.);
#824=ORIENTED_EDGE('',*,*,#823,.T.);
#825=ORIENTED_EDGE('',*,*,#590,.T.);
#826=ORIENTED_EDGE('',*,*,#792,.F.);
#827=EDGE_LOOP('',(#817,#824,#825,#826));
#828=FACE_BOUND('',#827,.T.);
#829=ADVANCED_FACE('F658',(#828),#809,.F.);
#830=CARTESIAN_POINT('',(165.1,-12.7,-38.1));
#831=DIRECTION('',(0.,-1.,0.));
#832=DIRECTION('',(0.,0.,-1.));
#833=AXIS2_PLACEMENT_3D('',#830,#831,#832);
#834=TOROIDAL_SURFACE('',#833,20.1959236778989,6.35);
#835=CARTESIAN_POINT('',(185.295923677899,-12.7,-38.1));
#836=DIRECTION('',(0.,0.,-1.));
#837=DIRECTION('',(-1.,0.,0.));
#838=AXIS2_PLACEMENT_3D('',#835,#836,#837);
#839=CIRCLE('',#838,6.35);
#840=CARTESIAN_POINT('',(185.295923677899,-19.05,-38.1));
#841=VERTEX_POINT('',#840);
#842=EDGE_CURVE('E315',#841,#815,#839,.T.);
#843=ORIENTED_EDGE('',*,*,#842,.F.);
#844=CARTESIAN_POINT('',(165.1,-19.05,-38.1));
#845=DIRECTION('',(0.,-1.,0.));
#846=DIRECTION('',(0.,0.,-1.));
#847=AXIS2_PLACEMENT_3D('',#844,#845,#846);
#848=CIRCLE('',#847,20.1959236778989);
#849=EDGE_CURVE('E408',#841,#614,#848,.T.);
#850=ORIENTED_EDGE('',*,*,#849,.T.);
#851=ORIENTED_EDGE('',*,*,#615,.T.);
#852=ORIENTED_EDGE('',*,*,#823,.F.);
#853=EDGE_LOOP('',(#843,#850,#851,#852));
#854=FACE_BOUND('',#853,.T.);
#855=ADVANCED_FACE('F664',(#854),#834,.T.);
#856=CARTESIAN_POINT('',(165.1,-12.7,-38.1));
#857=DIRECTION('',(0.,-1.,0.));
#858=DIRECTION('',(0.,0.,-1.));
#859=AXIS2_PLACEMENT_3D('',#856,#857,#858);
#860=TOROIDAL_SURFACE('',#859,56.004076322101,6.35);
#861=CARTESIAN_POINT('',(221.104076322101,-12.7,-38.1));
#862=DIRECTION('',(0.,0.,-1.));
#863=DIRECTION('',(1.,0.,0.));
#864=AXIS2_PLACEMENT_3D('',#861,#862,#863);
#865=CIRCLE('',#864,6.35);
#866=CARTESIAN_POINT('',(227.367677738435,-11.656066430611,-38.0999999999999));
#867=VERTEX_POINT('',#866);
#868=CARTESIAN_POINT('',(221.104076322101,-19.05,-38.1));
#869=VERTEX_POINT('',#868);
#870=EDGE_CURVE('E312',#867,#869,#865,.T.);
#871=ORIENTED_EDGE('',*,*,#870,.F.);
#872=CARTESIAN_POINT('',(165.1,-11.656066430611,-38.1));
#873=DIRECTION('',(0.,-1.,0.));
#874=DIRECTION('',(0.,0.,-1.));
#875=AXIS2_PLACEMENT_3D('',#872,#873,#874);
#876=CIRCLE('',#875,62.2676777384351);
#877=EDGE_CURVE('E402',#867,#639,#876,.T.);
#878=ORIENTED_EDGE('',*,*,#877,.T.);
#879=ORIENTED_EDGE('',*,*,#642,.T.);
#880=CARTESIAN_POINT('',(165.1,-19.05,-38.1));
#881=DIRECTION('',(0.,-1.,0.));
#882=DIRECTION('',(0.,0.,-1.));
#883=AXIS2_PLACEMENT_3D('',#880,#881,#882);
#884=CIRCLE('',#883,56.004076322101);
#885=EDGE_CURVE('E405',#869,#641,#884,.T.);
#886=ORIENTED_EDGE('',*,*,#885,.F.);
#887=EDGE_LOOP('',(#871,#878,#879,#886));
#888=FACE_BOUND('',#887,.T.);
#889=ADVANCED_FACE('F689',(#888),#860,.T.);
#890=CARTESIAN_POINT('',(165.1,13.743933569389,-38.1));
#891=DIRECTION('',(0.,-1.,0.));
#892=DIRECTION('',(0.,0.,-1.));
#893=AXIS2_PLACEMENT_3D('',#890,#891,#892);
#894=CONICAL_SURFACE('',#893,58.0343444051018,0.165148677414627);
#895=DIRECTION('',(0.164398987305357,-0.986393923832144,0.));
#896=VECTOR('',#895,1.);
#897=CARTESIAN_POINT('',(223.134344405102,13.743933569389,-38.1));
#898=LINE('',#897,#896);
#899=CARTESIAN_POINT('',(223.134344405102,13.743933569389,-38.1));
#900=VERTEX_POINT('',#899);
#901=EDGE_CURVE('E309',#900,#867,#898,.T.);
#902=ORIENTED_EDGE('',*,*,#901,.F.);
#903=CARTESIAN_POINT('',(165.1,13.743933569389,-38.1));
#904=DIRECTION('',(0.,-1.,0.));
#905=DIRECTION('',(0.,0.,-1.));
#906=AXIS2_PLACEMENT_3D('',#903,#904,#905);
#907=CIRCLE('',#906,58.0343444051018);
#908=EDGE_CURVE('E392',#900,#670,#907,.T.);
#909=ORIENTED_EDGE('',*,*,#908,.T.);
#910=ORIENTED_EDGE('',*,*,#671,.T.);
#911=ORIENTED_EDGE('',*,*,#877,.F.);
#912=EDGE_LOOP('',(#902,#909,#910,#911));
#913=FACE_BOUND('',#912,.T.);
#914=ADVANCED_FACE('F687',(#913),#894,.T.);
#915=CARTESIAN_POINT('',(165.1,12.7,-38.1));
#916=DIRECTION('',(0.,-1.,0.));
#917=DIRECTION('',(0.,0.,-1.));
#918=AXIS2_PLACEMENT_3D('',#915,#916,#917);
#919=TOROIDAL_SURFACE('',#918,51.7707429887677,6.35);
#920=CARTESIAN_POINT('',(216.870742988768,12.7,-38.1));
#921=DIRECTION('',(0.,0.,-1.));
#922=DIRECTION('',(-1.,0.,0.));
#923=AXIS2_PLACEMENT_3D('',#920,#921,#922);
#924=CIRCLE('',#923,6.35);
#925=CARTESIAN_POINT('',(216.870742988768,19.05,-38.1));
#926=VERTEX_POINT('',#925);
#927=EDGE_CURVE('E301',#926,#900,#924,.T.);
#928=ORIENTED_EDGE('',*,*,#927,.F.);
#929=CARTESIAN_POINT('',(165.1,19.05,-38.1));
#930=DIRECTION('',(0.,-1.,0.));
#931=DIRECTION('',(0.,0.,-1.));
#932=AXIS2_PLACEMENT_3D('',#929,#930,#931);
#933=CIRCLE('',#932,51.7707429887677);
#934=EDGE_CURVE('E420',#926,#695,#933,.T.);
#935=ORIENTED_EDGE('',*,*,#934,.T.);
#936=ORIENTED_EDGE('',*,*,#696,.T.);
#937=ORIENTED_EDGE('',*,*,#908,.F.);
#938=EDGE_LOOP('',(#928,#935,#936,#937));
#939=FACE_BOUND('',#938,.T.);
#940=ADVANCED_FACE('F634',(#939),#919,.T.);
#941=CARTESIAN_POINT('',(165.1,0.,-38.1));
#942=DIRECTION('',(0.,-1.,0.));
#943=DIRECTION('',(0.,0.,-1.));
#944=AXIS2_PLACEMENT_3D('',#941,#942,#943);
#945=CYLINDRICAL_SURFACE('',#944,50.8000000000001);
#946=DIRECTION('',(0.,-1.,0.));
#947=VECTOR('',#946,1.);
#948=CARTESIAN_POINT('',(215.9,-12.7,-38.1));
#949=LINE('',#948,#947);
#950=CARTESIAN_POINT('',(215.9,12.7,-38.1));
#951=VERTEX_POINT('',#950);
#952=CARTESIAN_POINT('',(215.9,-12.7,-38.1));
#953=VERTEX_POINT('',#952);
#954=EDGE_CURVE('E297',#951,#953,#949,.T.);
#955=ORIENTED_EDGE('',*,*,#954,.T.);
#956=CARTESIAN_POINT('',(165.1,-12.7,-38.1));
#957=DIRECTION('',(0.,-1.,0.));
#958=DIRECTION('',(0.,0.,-1.));
#959=AXIS2_PLACEMENT_3D('',#956,#957,#958);
#960=CIRCLE('',#959,50.8000000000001);
#961=EDGE_CURVE('E279',#953,#721,#960,.T.);
#962=ORIENTED_EDGE('',*,*,#961,.T.);
#963=ORIENTED_EDGE('',*,*,#722,.F.);
#964=CARTESIAN_POINT('',(165.1,12.7,-38.1));
#965=DIRECTION('',(0.,-1.,0.));
#966=DIRECTION('',(0.,0.,-1.));
#967=AXIS2_PLACEMENT_3D('',#964,#965,#966);
#968=CIRCLE('',#967,50.8000000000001);
#969=EDGE_CURVE('E396',#951,#719,#968,.T.);
#970=ORIENTED_EDGE('',*,*,#969,.F.);
#971=EDGE_LOOP('',(#955,#962,#963,#970));
#972=FACE_BOUND('',#971,.T.);
#973=ADVANCED_FACE('F789',(#972),#945,.F.);
#974=CARTESIAN_POINT('',(165.1,0.,-38.1));
#975=DIRECTION('',(0.,-1.,0.));
#976=DIRECTION('',(0.,0.,-1.));
#977=AXIS2_PLACEMENT_3D('',#974,#975,#976);
#978=CYLINDRICAL_SURFACE('',#977,25.4000000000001);
#979=DIRECTION('',(0.,1.,0.));
#980=VECTOR('',#979,1.);
#981=CARTESIAN_POINT('',(190.5,-12.7,-38.1));
#982=LINE('',#981,#980);
#983=CARTESIAN_POINT('',(190.5,-12.7,-38.1));
#984=VERTEX_POINT('',#983);
#985=CARTESIAN_POINT('',(190.5,12.7,-38.1));
#986=VERTEX_POINT('',#985);
#987=EDGE_CURVE('E273',#984,#986,#982,.T.);
#988=ORIENTED_EDGE('',*,*,#987,.T.);
#989=CARTESIAN_POINT('',(165.1,12.7,-38.1));
#990=DIRECTION('',(0.,-1.,0.));
#991=DIRECTION('',(0.,0.,-1.));
#992=AXIS2_PLACEMENT_3D('',#989,#990,#991);
#993=CIRCLE('',#992,25.4000000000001);
#994=EDGE_CURVE('E378',#986,#752,#993,.T.);
#995=ORIENTED_EDGE('',*,*,#994,.T.);
#996=ORIENTED_EDGE('',*,*,#753,.F.);
#997=CARTESIAN_POINT('',(165.1,-12.7,-38.1));
#998=DIRECTION('',(0.,-1.,0.));
#999=DIRECTION('',(0.,0.,-1.));
#1000=AXIS2_PLACEMENT_3D('',#997,#998,#999);
#1001=CIRCLE('',#1000,25.4000000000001);
#1002=EDGE_CURVE('E268',#984,#750,#1001,.T.);
#1003=ORIENTED_EDGE('',*,*,#1002,.F.);
#1004=EDGE_LOOP('',(#988,#995,#996,#1003));
#1005=FACE_BOUND('',#1004,.T.);
#1006=ADVANCED_FACE('F270',(#1005),#978,.T.);
#1007=CARTESIAN_POINT('',(216.870742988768,12.7,-38.1));
#1008=DIRECTION('',(0.,0.,-1.));
#1009=DIRECTION('',(-1.,0.,0.));
#1010=AXIS2_PLACEMENT_3D('',#1007,#1008,#1009);
#1011=CYLINDRICAL_SURFACE('',#1010,6.35);
#1012=CARTESIAN_POINT('',(216.870742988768,12.7,-63.5));
#1013=DIRECTION('',(0.,0.,-1.));
#1014=DIRECTION('',(-1.,0.,0.));
#1015=AXIS2_PLACEMENT_3D('',#1012,#1013,#1014);
#1016=CIRCLE('',#1015,6.35);
#1017=CARTESIAN_POINT('',(216.870742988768,19.05,-63.5));
#1018=VERTEX_POINT('',#1017);
#1019=CARTESIAN_POINT('',(223.134344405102,13.743933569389,-63.5));
#1020=VERTEX_POINT('',#1019);
#1021=EDGE_CURVE('E330',#1018,#1020,#1016,.T.);
#1022=ORIENTED_EDGE('',*,*,#1021,.F.);
#1023=DIRECTION('',(0.,0.,-1.));
#1024=VECTOR('',#1023,1.);
#1025=CARTESIAN_POINT('',(216.870742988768,19.05,-38.1));
#1026=LINE('',#1025,#1024);
#1027=EDGE_CURVE('E350',#926,#1018,#1026,.T.);
#1028=ORIENTED_EDGE('',*,*,#1027,.F.);
#1029=ORIENTED_EDGE('',*,*,#927,.T.);
#1030=DIRECTION('',(0.,0.,-1.));
#1031=VECTOR('',#1030,1.);
#1032=CARTESIAN_POINT('',(223.134344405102,13.743933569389,-38.1));
#1033=LINE('',#1032,#1031);
#1034=EDGE_CURVE('E364',#900,#1020,#1033,.T.);
#1035=ORIENTED_EDGE('',*,*,#1034,.T.);
#1036=EDGE_LOOP('',(#1022,#1028,#1029,#1035));
#1037=FACE_BOUND('',#1036,.T.);
#1038=ADVANCED_FACE('F639',(#1037),#1011,.T.);
#1039=CARTESIAN_POINT('',(216.870742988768,19.05,-38.1));
#1040=DIRECTION('',(0.,1.,0.));
#1041=DIRECTION('',(-1.,0.,0.));
#1042=AXIS2_PLACEMENT_3D('',#1039,#1040,#1041);
#1043=PLANE('',#1042);
#1044=DIRECTION('',(1.,0.,0.));
#1045=VECTOR('',#1044,1.);
#1046=CARTESIAN_POINT('',(216.870742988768,19.05,-63.5));
#1047=LINE('',#1046,#1045);
#1048=CARTESIAN_POINT('',(189.529257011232,19.05,-63.5));
#1049=VERTEX_POINT('',#1048);
#1050=EDGE_CURVE('E298',#1049,#1018,#1047,.T.);
#1051=ORIENTED_EDGE('',*,*,#1050,.F.);
#1052=DIRECTION('',(0.,0.,-1.));
#1053=VECTOR('',#1052,1.);
#1054=CARTESIAN_POINT('',(189.529257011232,19.05,-38.1));
#1055=LINE('',#1054,#1053);
#1056=EDGE_CURVE('E352',#784,#1049,#1055,.T.);
#1057=ORIENTED_EDGE('',*,*,#1056,.F.);
#1058=ORIENTED_EDGE('',*,*,#800,.T.);
#1059=ORIENTED_EDGE('',*,*,#574,.T.);
#1060=ORIENTED_EDGE('',*,*,#340,.T.);
#1061=ORIENTED_EDGE('',*,*,#56,.T.);
#1062=DIRECTION('',(-1.,0.,0.));
#1063=VECTOR('',#1062,1.);
#1064=CARTESIAN_POINT('',(-216.870742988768,19.05,-63.5));
#1065=LINE('',#1064,#1063);
#1066=EDGE_CURVE('E48',#49,#217,#1065,.T.);
#1067=ORIENTED_EDGE('',*,*,#1066,.T.);
#1068=ORIENTED_EDGE('',*,*,#218,.F.);
#1069=ORIENTED_EDGE('',*,*,#474,.F.);
#1070=ORIENTED_EDGE('',*,*,#702,.F.);
#1071=ORIENTED_EDGE('',*,*,#934,.F.);
#1072=ORIENTED_EDGE('',*,*,#1027,.T.);
#1073=EDGE_LOOP('',(#1051,#1057,#1058,#1059,#1060,#1061,#1067,#1068,#1069,#1070,#1071,#1072));
#1074=FACE_BOUND('',#1073,.T.);
#1075=ADVANCED_FACE('F597',(#1074),#1043,.T.);
#1076=CARTESIAN_POINT('',(189.529257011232,12.7,-38.1));
#1077=DIRECTION('',(0.,0.,-1.));
#1078=DIRECTION('',(-1.,0.,0.));
#1079=AXIS2_PLACEMENT_3D('',#1076,#1077,#1078);
#1080=CYLINDRICAL_SURFACE('',#1079,6.35);
#1081=CARTESIAN_POINT('',(189.529257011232,12.7,-63.5));
#1082=DIRECTION('',(0.,0.,-1.));
#1083=DIRECTION('',(1.,0.,0.));
#1084=AXIS2_PLACEMENT_3D('',#1081,#1082,#1083);
#1085=CIRCLE('',#1084,6.35);
#1086=CARTESIAN_POINT('',(183.265655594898,13.743933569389,-63.5));
#1087=VERTEX_POINT('',#1086);
#1088=EDGE_CURVE('E304',#1087,#1049,#1085,.T.);
#1089=ORIENTED_EDGE('',*,*,#1088,.F.);
#1090=DIRECTION('',(0.,0.,-1.));
#1091=VECTOR('',#1090,1.);
#1092=CARTESIAN_POINT('',(183.265655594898,13.743933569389,-38.1));
#1093=LINE('',#1092,#1091);
#1094=EDGE_CURVE('E354',#782,#1087,#1093,.T.);
#1095=ORIENTED_EDGE('',*,*,#1094,.F.);
#1096=ORIENTED_EDGE('',*,*,#785,.T.);
#1097=ORIENTED_EDGE('',*,*,#1056,.T.);
#1098=EDGE_LOOP('',(#1089,#1095,#1096,#1097));
#1099=FACE_BOUND('',#1098,.T.);
#1100=ADVANCED_FACE('F648',(#1099),#1080,.T.);
#1101=CARTESIAN_POINT('',(179.032322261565,-11.656066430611,-38.1000000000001));
#1102=DIRECTION('',(-0.986393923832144,0.164398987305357,0.));
#1103=DIRECTION('',(-0.164398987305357,-0.986393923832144,0.));
#1104=AXIS2_PLACEMENT_3D('',#1101,#1102,#1103);
#1105=PLANE('',#1104);
#1106=DIRECTION('',(0.164398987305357,0.986393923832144,0.));
#1107=VECTOR('',#1106,1.);
#1108=CARTESIAN_POINT('',(179.032322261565,-11.656066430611,-63.5000000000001));
#1109=LINE('',#1108,#1107);
#1110=CARTESIAN_POINT('',(179.032322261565,-11.656066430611,-63.5000000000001));
#1111=VERTEX_POINT('',#1110);
#1112=EDGE_CURVE('E345',#1111,#1087,#1109,.T.);
#1113=ORIENTED_EDGE('',*,*,#1112,.F.);
#1114=DIRECTION('',(0.,0.,-1.));
#1115=VECTOR('',#1114,1.);
#1116=CARTESIAN_POINT('',(179.032322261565,-11.656066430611,-38.1000000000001));
#1117=LINE('',#1116,#1115);
#1118=EDGE_CURVE('E356',#815,#1111,#1117,.T.);
#1119=ORIENTED_EDGE('',*,*,#1118,.F.);
#1120=ORIENTED_EDGE('',*,*,#816,.T.);
#1121=ORIENTED_EDGE('',*,*,#1094,.T.);
#1122=EDGE_LOOP('',(#1113,#1119,#1120,#1121));
#1123=FACE_BOUND('',#1122,.T.);
#1124=ADVANCED_FACE('F703',(#1123),#1105,.T.);
#1125=CARTESIAN_POINT('',(185.295923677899,-12.7,-38.1));
#1126=DIRECTION('',(0.,0.,-1.));
#1127=DIRECTION('',(-1.,0.,0.));
#1128=AXIS2_PLACEMENT_3D('',#1125,#1126,#1127);
#1129=CYLINDRICAL_SURFACE('',#1128,6.35);
#1130=CARTESIAN_POINT('',(185.295923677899,-12.7,-63.5));
#1131=DIRECTION('',(0.,0.,-1.));
#1132=DIRECTION('',(-1.,0.,0.));
#1133=AXIS2_PLACEMENT_3D('',#1130,#1131,#1132);
#1134=CIRCLE('',#1133,6.35);
#1135=CARTESIAN_POINT('',(185.295923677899,-19.05,-63.5));
#1136=VERTEX_POINT('',#1135);
#1137=EDGE_CURVE('E342',#1136,#1111,#1134,.T.);
#1138=ORIENTED_EDGE('',*,*,#1137,.F.);
#1139=DIRECTION('',(0.,0.,-1.));
#1140=VECTOR('',#1139,1.);
#1141=CARTESIAN_POINT('',(185.295923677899,-19.05,-38.1));
#1142=LINE('',#1141,#1140);
#1143=EDGE_CURVE('E358',#841,#1136,#1142,.T.);
#1144=ORIENTED_EDGE('',*,*,#1143,.F.);
#1145=ORIENTED_EDGE('',*,*,#842,.T.);
#1146=ORIENTED_EDGE('',*,*,#1118,.T.);
#1147=EDGE_LOOP('',(#1138,#1144,#1145,#1146));
#1148=FACE_BOUND('',#1147,.T.);
#1149=ADVANCED_FACE('F700',(#1148),#1129,.T.);
#1150=CARTESIAN_POINT('',(221.104076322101,-19.05,-38.1));
#1151=DIRECTION('',(0.,-1.,0.));
#1152=DIRECTION('',(1.,0.,0.));
#1153=AXIS2_PLACEMENT_3D('',#1150,#1151,#1152);
#1154=PLANE('',#1153);
#1155=DIRECTION('',(-1.,0.,0.));
#1156=VECTOR('',#1155,1.);
#1157=CARTESIAN_POINT('',(221.104076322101,-19.05,-63.5));
#1158=LINE('',#1157,#1156);
#1159=CARTESIAN_POINT('',(221.104076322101,-19.05,-63.5));
#1160=VERTEX_POINT('',#1159);
#1161=EDGE_CURVE('E339',#1160,#1136,#1158,.T.);
#1162=ORIENTED_EDGE('',*,*,#1161,.F.);
#1163=DIRECTION('',(0.,0.,-1.));
#1164=VECTOR('',#1163,1.);
#1165=CARTESIAN_POINT('',(221.104076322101,-19.05,-38.1));
#1166=LINE('',#1165,#1164);
#1167=EDGE_CURVE('E360',#869,#1160,#1166,.T.);
#1168=ORIENTED_EDGE('',*,*,#1167,.F.);
#1169=ORIENTED_EDGE('',*,*,#885,.T.);
#1170=ORIENTED_EDGE('',*,*,#655,.T.);
#1171=ORIENTED_EDGE('',*,*,#425,.T.);
#1172=ORIENTED_EDGE('',*,*,#162,.T.);
#1173=DIRECTION('',(1.,0.,0.));
#1174=VECTOR('',#1173,1.);
#1175=CARTESIAN_POINT('',(-221.104076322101,-19.05,-63.5000000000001));
#1176=LINE('',#1175,#1174);
#1177=EDGE_CURVE('E562',#155,#111,#1176,.T.);
#1178=ORIENTED_EDGE('',*,*,#1177,.T.);
#1179=ORIENTED_EDGE('',*,*,#112,.F.);
#1180=ORIENTED_EDGE('',*,*,#389,.F.);
#1181=ORIENTED_EDGE('',*,*,#621,.F.);
#1182=ORIENTED_EDGE('',*,*,#849,.F.);
#1183=ORIENTED_EDGE('',*,*,#1143,.T.);
#1184=EDGE_LOOP('',(#1162,#1168,#1169,#1170,#1171,#1172,#1178,#1179,#1180,#1181,#1182,#1183));
#1185=FACE_BOUND('',#1184,.T.);
#1186=ADVANCED_FACE('F669',(#1185),#1154,.T.);
#1187=CARTESIAN_POINT('',(221.104076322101,-12.7,-38.1));
#1188=DIRECTION('',(0.,0.,-1.));
#1189=DIRECTION('',(-1.,0.,0.));
#1190=AXIS2_PLACEMENT_3D('',#1187,#1188,#1189);
#1191=CYLINDRICAL_SURFACE('',#1190,6.35);
#1192=CARTESIAN_POINT('',(221.104076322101,-12.7,-63.5));
#1193=DIRECTION('',(0.,0.,-1.));
#1194=DIRECTION('',(1.,0.,0.));
#1195=AXIS2_PLACEMENT_3D('',#1192,#1193,#1194);
#1196=CIRCLE('',#1195,6.35);
#1197=CARTESIAN_POINT('',(227.367677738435,-11.656066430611,-63.4999999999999));
#1198=VERTEX_POINT('',#1197);
#1199=EDGE_CURVE('E336',#1198,#1160,#1196,.T.);
#1200=ORIENTED_EDGE('',*,*,#1199,.F.);
#1201=DIRECTION('',(0.,0.,-1.));
#1202=VECTOR('',#1201,1.);
#1203=CARTESIAN_POINT('',(227.367677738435,-11.656066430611,-38.0999999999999));
#1204=LINE('',#1203,#1202);
#1205=EDGE_CURVE('E362',#867,#1198,#1204,.T.);
#1206=ORIENTED_EDGE('',*,*,#1205,.F.);
#1207=ORIENTED_EDGE('',*,*,#870,.T.);
#1208=ORIENTED_EDGE('',*,*,#1167,.T.);
#1209=EDGE_LOOP('',(#1200,#1206,#1207,#1208));
#1210=FACE_BOUND('',#1209,.T.);
#1211=ADVANCED_FACE('F694',(#1210),#1191,.T.);
#1212=CARTESIAN_POINT('',(190.5,-12.7,-38.1));
#1213=DIRECTION('',(-1.,0.,0.));
#1214=DIRECTION('',(0.,0.,1.));
#1215=AXIS2_PLACEMENT_3D('',#1212,#1213,#1214);
#1216=PLANE('',#1215);
#1217=DIRECTION('',(0.,1.,0.));
#1218=VECTOR('',#1217,1.);
#1219=CARTESIAN_POINT('',(190.5,-12.7,-63.5));
#1220=LINE('',#1219,#1218);
#1221=CARTESIAN_POINT('',(190.5,-12.7,-63.5));
#1222=VERTEX_POINT('',#1221);
#1223=CARTESIAN_POINT('',(190.5,12.7,-63.5));
#1224=VERTEX_POINT('',#1223);
#1225=EDGE_CURVE('E323',#1222,#1224,#1220,.T.);
#1226=ORIENTED_EDGE('',*,*,#1225,.T.);
#1227=DIRECTION('',(0.,0.,-1.));
#1228=VECTOR('',#1227,1.);
#1229=CARTESIAN_POINT('',(190.5,12.7,-38.1));
#1230=LINE('',#1229,#1228);
#1231=EDGE_CURVE('E296',#986,#1224,#1230,.T.);
#1232=ORIENTED_EDGE('',*,*,#1231,.F.);
#1233=ORIENTED_EDGE('',*,*,#987,.F.);
#1234=DIRECTION('',(0.,0.,-1.));
#1235=VECTOR('',#1234,1.);
#1236=CARTESIAN_POINT('',(190.5,-12.7,-38.1));
#1237=LINE('',#1236,#1235);
#1238=EDGE_CURVE('E283',#984,#1222,#1237,.T.);
#1239=ORIENTED_EDGE('',*,*,#1238,.T.);
#1240=EDGE_LOOP('',(#1226,#1232,#1233,#1239));
#1241=FACE_BOUND('',#1240,.T.);
#1242=ADVANCED_FACE('F294',(#1241),#1216,.F.);
#1243=CARTESIAN_POINT('',(215.9,12.7,-38.1));
#1244=DIRECTION('',(0.,1.,0.));
#1245=DIRECTION('',(0.,0.,1.));
#1246=AXIS2_PLACEMENT_3D('',#1243,#1244,#1245);
#1247=PLANE('',#1246);
#1248=DIRECTION('',(1.,0.,0.));
#1249=VECTOR('',#1248,1.);
#1250=CARTESIAN_POINT('',(215.9,12.7,-63.5));
#1251=LINE('',#1250,#1249);
#1252=CARTESIAN_POINT('',(215.9,12.7,-63.5));
#1253=VERTEX_POINT('',#1252);
#1254=EDGE_CURVE('E328',#1224,#1253,#1251,.T.);
#1255=ORIENTED_EDGE('',*,*,#1254,.T.);
#1256=DIRECTION('',(0.,0.,-1.));
#1257=VECTOR('',#1256,1.);
#1258=CARTESIAN_POINT('',(215.9,12.7,-38.1));
#1259=LINE('',#1258,#1257);
#1260=EDGE_CURVE('E367',#951,#1253,#1259,.T.);
#1261=ORIENTED_EDGE('',*,*,#1260,.F.);
#1262=ORIENTED_EDGE('',*,*,#969,.T.);
#1263=ORIENTED_EDGE('',*,*,#735,.T.);
#1264=ORIENTED_EDGE('',*,*,#509,.T.);
#1265=ORIENTED_EDGE('',*,*,#266,.T.);
#1266=DIRECTION('',(-1.,0.,0.));
#1267=VECTOR('',#1266,1.);
#1268=CARTESIAN_POINT('',(-215.9,12.7,-63.5));
#1269=LINE('',#1268,#1267);
#1270=EDGE_CURVE('E551',#291,#259,#1269,.T.);
#1271=ORIENTED_EDGE('',*,*,#1270,.F.);
#1272=ORIENTED_EDGE('',*,*,#292,.F.);
#1273=ORIENTED_EDGE('',*,*,#534,.F.);
#1274=ORIENTED_EDGE('',*,*,#759,.F.);
#1275=ORIENTED_EDGE('',*,*,#994,.F.);
#1276=ORIENTED_EDGE('',*,*,#1231,.T.);
#1277=EDGE_LOOP('',(#1255,#1261,#1262,#1263,#1264,#1265,#1271,#1272,#1273,#1274,#1275,#1276));
#1278=FACE_BOUND('',#1277,.T.);
#1279=ADVANCED_FACE('F797',(#1278),#1247,.F.);
#1280=CARTESIAN_POINT('',(215.9,-12.7,-38.1));
#1281=DIRECTION('',(1.,0.,0.));
#1282=DIRECTION('',(0.,0.,-1.));
#1283=AXIS2_PLACEMENT_3D('',#1280,#1281,#1282);
#1284=PLANE('',#1283);
#1285=DIRECTION('',(0.,-1.,0.));
#1286=VECTOR('',#1285,1.);
#1287=CARTESIAN_POINT('',(215.9,-12.7,-63.5));
#1288=LINE('',#1287,#1286);
#1289=CARTESIAN_POINT('',(215.9,-12.7,-63.5));
#1290=VERTEX_POINT('',#1289);
#1291=EDGE_CURVE('E326',#1253,#1290,#1288,.T.);
#1292=ORIENTED_EDGE('',*,*,#1291,.T.);
#1293=DIRECTION('',(0.,0.,-1.));
#1294=VECTOR('',#1293,1.);
#1295=CARTESIAN_POINT('',(215.9,-12.7,-38.1));
#1296=LINE('',#1295,#1294);
#1297=EDGE_CURVE('E291',#953,#1290,#1296,.T.);
#1298=ORIENTED_EDGE('',*,*,#1297,.F.);
#1299=ORIENTED_EDGE('',*,*,#954,.F.);
#1300=ORIENTED_EDGE('',*,*,#1260,.T.);
#1301=EDGE_LOOP('',(#1292,#1298,#1299,#1300));
#1302=FACE_BOUND('',#1301,.T.);
#1303=ADVANCED_FACE('F800',(#1302),#1284,.F.);
#1304=CARTESIAN_POINT('',(215.9,-12.7,-38.1));
#1305=DIRECTION('',(0.,-1.,0.));
#1306=DIRECTION('',(0.,0.,-1.));
#1307=AXIS2_PLACEMENT_3D('',#1304,#1305,#1306);
#1308=PLANE('',#1307);
#1309=DIRECTION('',(-1.,0.,0.));
#1310=VECTOR('',#1309,1.);
#1311=CARTESIAN_POINT('',(215.9,-12.7,-63.5));
#1312=LINE('',#1311,#1310);
#1313=EDGE_CURVE('E287',#1290,#1222,#1312,.T.);
#1314=ORIENTED_EDGE('',*,*,#1313,.T.);
#1315=ORIENTED_EDGE('',*,*,#1238,.F.);
#1316=ORIENTED_EDGE('',*,*,#1002,.T.);
#1317=ORIENTED_EDGE('',*,*,#766,.T.);
#1318=ORIENTED_EDGE('',*,*,#542,.T.);
#1319=ORIENTED_EDGE('',*,*,#306,.T.);
#1320=DIRECTION('',(1.,0.,0.));
#1321=VECTOR('',#1320,1.);
#1322=CARTESIAN_POINT('',(-215.9,-12.7,-63.5));
#1323=LINE('',#1322,#1321);
#1324=EDGE_CURVE('E545',#251,#299,#1323,.T.);
#1325=ORIENTED_EDGE('',*,*,#1324,.F.);
#1326=ORIENTED_EDGE('',*,*,#252,.F.);
#1327=ORIENTED_EDGE('',*,*,#501,.F.);
#1328=ORIENTED_EDGE('',*,*,#728,.F.);
#1329=ORIENTED_EDGE('',*,*,#961,.F.);
#1330=ORIENTED_EDGE('',*,*,#1297,.T.);
#1331=EDGE_LOOP('',(#1314,#1315,#1316,#1317,#1318,#1319,#1325,#1326,#1327,#1328,#1329,#1330));
#1332=FACE_BOUND('',#1331,.T.);
#1333=ADVANCED_FACE('F284',(#1332),#1308,.F.);
#1334=CARTESIAN_POINT('',(223.134344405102,13.743933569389,-38.1));
#1335=DIRECTION('',(0.986393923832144,0.164398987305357,0.));
#1336=DIRECTION('',(-0.164398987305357,0.986393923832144,0.));
#1337=AXIS2_PLACEMENT_3D('',#1334,#1335,#1336);
#1338=PLANE('',#1337);
#1339=DIRECTION('',(0.164398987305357,-0.986393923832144,0.));
#1340=VECTOR('',#1339,1.);
#1341=CARTESIAN_POINT('',(223.134344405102,13.743933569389,-63.5));
#1342=LINE('',#1341,#1340);
#1343=EDGE_CURVE('E333',#1020,#1198,#1342,.T.);
#1344=ORIENTED_EDGE('',*,*,#1343,.F.);
#1345=ORIENTED_EDGE('',*,*,#1034,.F.);
#1346=ORIENTED_EDGE('',*,*,#901,.T.);
#1347=ORIENTED_EDGE('',*,*,#1205,.T.);
#1348=EDGE_LOOP('',(#1344,#1345,#1346,#1347));
#1349=FACE_BOUND('',#1348,.T.);
#1350=ADVANCED_FACE('F696',(#1349),#1338,.T.);
#1351=CARTESIAN_POINT('',(-216.870742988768,12.7,-63.5));
#1352=DIRECTION('',(0.,0.,1.));
#1353=DIRECTION('',(1.,0.,0.));
#1354=AXIS2_PLACEMENT_3D('',#1351,#1352,#1353);
#1355=PLANE('',#1354);
#1356=ORIENTED_EDGE('',*,*,#300,.T.);
#1357=ORIENTED_EDGE('',*,*,#1270,.T.);
#1358=ORIENTED_EDGE('',*,*,#260,.T.);
#1359=ORIENTED_EDGE('',*,*,#1324,.T.);
#1360=EDGE_LOOP('',(#1356,#1357,#1358,#1359));
#1361=FACE_BOUND('',#1360,.T.);
#1362=ORIENTED_EDGE('',*,*,#225,.F.);
#1363=ORIENTED_EDGE('',*,*,#1066,.F.);
#1364=ORIENTED_EDGE('',*,*,#50,.F.);
#1365=ORIENTED_EDGE('',*,*,#86,.F.);
#1366=ORIENTED_EDGE('',*,*,#119,.F.);
#1367=ORIENTED_EDGE('',*,*,#1177,.F.);
#1368=ORIENTED_EDGE('',*,*,#156,.F.);
#1369=ORIENTED_EDGE('',*,*,#192,.F.);
#1370=EDGE_LOOP('',(#1362,#1363,#1364,#1365,#1366,#1367,#1368,#1369));
#1371=FACE_BOUND('',#1370,.T.);
#1372=ADVANCED_FACE('F618',(#1361,#1371),#1355,.F.);
#1373=CARTESIAN_POINT('',(216.870742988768,12.7,-63.5));
#1374=DIRECTION('',(0.,0.,-1.));
#1375=DIRECTION('',(-1.,0.,0.));
#1376=AXIS2_PLACEMENT_3D('',#1373,#1374,#1375);
#1377=PLANE('',#1376);
#1378=ORIENTED_EDGE('',*,*,#1225,.F.);
#1379=ORIENTED_EDGE('',*,*,#1313,.F.);
#1380=ORIENTED_EDGE('',*,*,#1291,.F.);
#1381=ORIENTED_EDGE('',*,*,#1254,.F.);
#1382=EDGE_LOOP('',(#1378,#1379,#1380,#1381));
#1383=FACE_BOUND('',#1382,.T.);
#1384=ORIENTED_EDGE('',*,*,#1021,.T.);
#1385=ORIENTED_EDGE('',*,*,#1343,.T.);
#1386=ORIENTED_EDGE('',*,*,#1199,.T.);
#1387=ORIENTED_EDGE('',*,*,#1161,.T.);
#1388=ORIENTED_EDGE('',*,*,#1137,.T.);
#1389=ORIENTED_EDGE('',*,*,#1112,.T.);
#1390=ORIENTED_EDGE('',*,*,#1088,.T.);
#1391=ORIENTED_EDGE('',*,*,#1050,.T.);
#1392=EDGE_LOOP('',(#1384,#1385,#1386,#1387,#1388,#1389,#1390,#1391));
#1393=FACE_BOUND('',#1392,.T.);
#1394=ADVANCED_FACE('F643',(#1383,#1393),#1377,.T.);
#1395=CLOSED_SHELL('',(#60,#91,#124,#166,#197,#230,#270,#310,#344,#369,#395,#429,#454,#480,#513,
#546,#578,#602,#627,#659,#683,#708,#739,#770,#804,#829,#855,#889,#914,#940,#973,#1006,#1038,
#1075,#1100,#1124,#1149,#1186,#1211,#1242,#1279,#1303,#1333,#1350,#1372,#1394));
#1396=MANIFOLD_SOLID_BREP('B2',#1395);
#1397=ADVANCED_BREP_SHAPE_REPRESENTATION('',(#18,#1396),#14);
#1398=SHAPE_DEFINITION_REPRESENTATION(#9,#1397);
ENDSEC;
END-ISO-10303-21;
